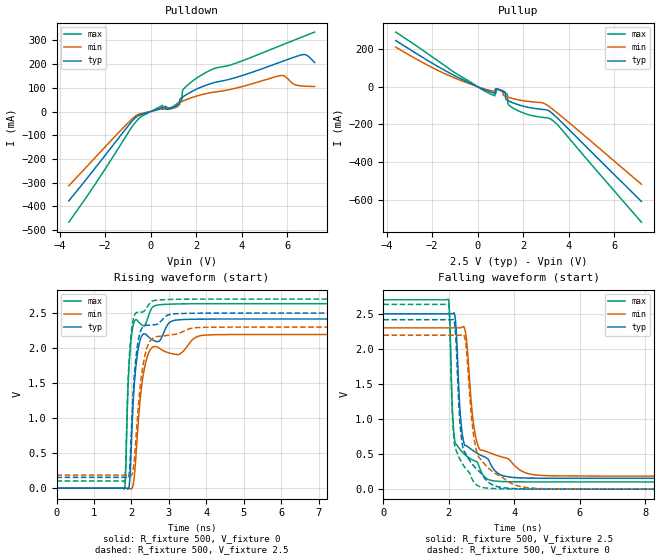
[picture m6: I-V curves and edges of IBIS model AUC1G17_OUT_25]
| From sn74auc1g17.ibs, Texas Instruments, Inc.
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[Model]   AUC1G17_OUT_25
Model_type  Output
Vref =   0
Rref =   500
Cref =   30p
Vmeas =   1.25
| variable   typ   min   max
C_comp   4.92pF   0.40pF   11.11pF
| C_pullup   5.21pF   0.40pF   11.11pF
| C_pulldown   4.64pF   0.49pF   6.59pF
[Temperature Range]   40   100   -40
| Ambient temperature   25   85   -40
[Voltage range]   2.5   2.3   2.7
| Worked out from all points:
|   slope of the pulldown table from 0 to 0.375 V, typ, clamps not added: 30.9 ohm
|   slope of the pullup table from 0 to 0.375 V, typ, clamps not added: 19.1 ohm
|   rising waveform, R_fixture 500, V_fixture 0: 20-80 % time 177ps typ, 248ps min, 128ps max; typ from 0 V to 2.42 V
|   falling waveform, R_fixture 500, V_fixture 2.5: 20-80 % time 235ps typ, 314ps min, 211ps max; typ from 2.5 V to 0.154 V
|   rising waveform, R_fixture 500, V_fixture 2.5: 20-80 % time 175ps typ, 246ps min, 126ps max; typ from 0.154 V to 2.5 V
|   falling waveform, R_fixture 500, V_fixture 0: 20-80 % time 304ps typ, 370ps min, 203ps max; typ from 2.42 V to 0 V
[Pulldown]
| AUC1G17_OUT_25
|   Voltage   I(typ)   I(min)   I(max)
-3.6V     -376.9mA   -313.1mA   -466.8mA
-450mV    -13.55mA   -9.198mA   -23.42mA
515mV     17.02mA    12.57mA    25.99mA
1.025V    18.9mA     15.4mA     23.61mA
1.27V     30.1mA     38.43mA    41.47mA
1.37V     59.42mA    42.49mA    49.07mA
1.395V    60.94mA    43.5mA     85.27mA
1.48V     66.06mA    46.86mA    98.94mA
2.54V     114.8mA    77.9mA     170.7mA
5.695V    208.5mA    151.4mA    277.9mA
6.74V     240.5mA    107.1mA    317.9mA
7.2V      207mA      105.8mA    335.2mA
[Pullup]
| AUC1G17_OUT_25
|   Voltage   I(typ)   I(min)   I(max)
-3.6V     245.6mA    210.5mA    290.4mA
295mV     -15.8mA    -11.56mA   -21.97mA
750mV     -34.5mA    -24.9mA    -48.13mA
770mV     -35.18mA   -25.36mA   -13.07mA
1.115V    -23.95mA   -20.34mA   -27.78mA
1.215V    -28.93mA   -50.57mA   -34.8mA
1.235V    -63.85mA   -51.41mA   -36.2mA
1.295V    -71.17mA   -53.86mA   -40.35mA
1.34V     -74.13mA   -55.63mA   -92.46mA
1.59V     -87.28mA   -64.24mA   -115.7mA
3.275V    -140.8mA   -117.4mA   -177.3mA
7.2V      -609.8mA   -518.6mA   -720mA
[Ramp]
| AUC1G17_OUT_25
| variable   typ   min   max
dV/dt_r   1.46/1.77E-10   1.33/2.49E-10   1.59/1.28E-10
dV/dt_f   1.42/2.34E-10   1.28/3.14E-10   1.56/2.09E-10
R_load = 500
[Rising Waveform]
| AUC1G17_OUT_25
R_fixture =   500
C_fixture =   0
L_fixture =   0
V_fixture =   0
V_fixture_min = 0
V_fixture_max = 0
|   Time   V(typ)   V(min)   V(max)
0s        8.521nV    24.59nV    1.794nV
1.81ns    228.4uV    -51.97uV   -8.382mV
1.84ns    2.634uV    -263.2uV   145.3mV
1.945ns   54.68mV    -3.046mV   1.809V
2.035ns   1.091V     18.31mV    2.292V
2.16ns    1.915V     768.5mV    2.395V
2.335ns   2.204V     1.675V     2.316V
2.71ns    2.093V     2.012V     2.616V
3.67ns    2.412V     2.138V     2.633V
34.99ns   2.416V     2.195V     2.634V
[Falling Waveform]
| AUC1G17_OUT_25
R_fixture =   500
C_fixture =   0
L_fixture =   0
V_fixture =   2.5
V_fixture_min = 2.3
V_fixture_max = 2.7
|   Time   V(typ)   V(min)   V(max)
0s        2.5V       2.3V       2.7V
1.99ns    2.5V       2.3V       2.705V
2.11ns    2.502V     2.3V       1.117V
2.19ns    2.454V     2.3V       662.6mV
2.345ns   1.098V     2.3V       564.7mV
2.465ns   648.7mV    2.31V      502mV
2.835ns   520.7mV    713.4mV    394mV
3.355ns   294.4mV    499.6mV    119.3mV
5.105ns   154.9mV    190.6mV    102.7mV
34.99ns   154.5mV    186.3mV    102.6mV
[Rising Waveform]
| AUC1G17_OUT_25
R_fixture =   500
C_fixture =   0
L_fixture =   0
V_fixture =   2.5
V_fixture_min = 2.3
V_fixture_max = 2.7
|   Time   V(typ)   V(min)   V(max)
0s        154.5mV    186.3mV    102.6mV
1.815ns   154.7mV    186.2mV    94.86mV
1.845ns   154.4mV    186.1mV    291.3mV
1.9ns     141.9mV    185.8mV    1.371V
1.94ns    196.8mV    184.9mV    1.837V
2.03ns    1.196V     215.2mV    2.359V
2.155ns   2.017V     958.3mV    2.51V
2.315ns   2.309V     1.767V     2.52V
2.65ns    2.335V     2.161V     2.682V
34.99ns   2.5V       2.3V       2.7V
[Falling Waveform]
| AUC1G17_OUT_25
R_fixture =   500
C_fixture =   0
L_fixture =   0
V_fixture =   0
V_fixture_min = 0
V_fixture_max = 0
|   Time   V(typ)   V(min)   V(max)
0s        2.416V     2.195V     2.634V
1.99ns    2.416V     2.195V     2.636V
2.105ns   2.417V     2.195V     1.087V
2.185ns   2.326V     2.195V     599.9mV
2.325ns   1.039V     2.195V     439.3mV
2.43ns    588.7mV    2.204V     350.4mV
2.79ns    315.8mV    671mV      85.72mV
3.095ns   152.9mV    355.5mV    19.4mV
5.05ns    284.1uV    4.26mV     -89.41uV
34.99ns   11.81uV    34.1nV     5.711uV
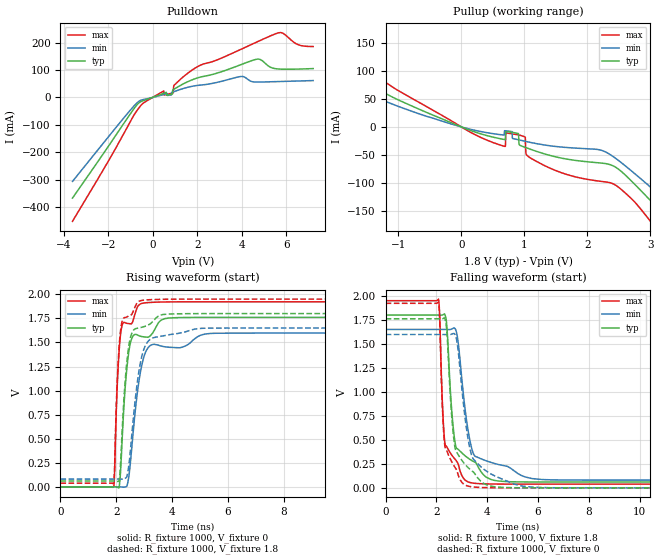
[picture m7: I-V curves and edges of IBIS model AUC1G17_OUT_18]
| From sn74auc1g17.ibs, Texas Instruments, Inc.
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[Model]   AUC1G17_OUT_18
Model_type  Output
Vref =   0
Rref =   1000
Cref =   30p
Vmeas =   0.9
| variable   typ   min   max
C_comp   5.30pF   0.54pF   7.90pF
| C_pullup   4.83pF   0.54pF   7.90pF
| C_pulldown   5.77pF   2.99pF   7.75pF
[Temperature Range]   40   100   -40
| Ambient temperature   25   85   -40
[Voltage range]   1.8   1.65   1.95
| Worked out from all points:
|   slope of the pulldown table from 0 to 0.27 V, typ, clamps not added: 34.4 ohm
|   slope of the pullup table from 0 to 0.27 V, typ, clamps not added: 24.6 ohm
|   rising waveform, R_fixture 1000, V_fixture 0: 20-80 % time 264ps typ, 398ps min, 176ps max; typ from 0 V to 1.76 V
|   falling waveform, R_fixture 1000, V_fixture 1.8: 20-80 % time 341ps typ, 479ps min, 266ps max; typ from 1.8 V to 0.061 V
|   rising waveform, R_fixture 1000, V_fixture 1.8: 20-80 % time 260ps typ, 387ps min, 172ps max; typ from 0.061 V to 1.8 V
|   falling waveform, R_fixture 1000, V_fixture 0: 20-80 % time 383ps typ, 501ps min, 259ps max; typ from 1.76 V to 0 V
[Pulldown]
| AUC1G17_OUT_18
|   Voltage   I(typ)   I(min)   I(max)
-3.6V     -366.8mA   -306mA     -451.3mA
-840mV    -41.02mA   -31.27mA   -64.29mA
-415mV    -11.62mA   -7.635mA   -20.14mA
495mV     14.95mA    10.62mA    23.51mA
885mV     12.29mA    19.09mA    15.87mA
925mV     28.57mA    20.19mA    16.9mA
960mV     30.15mA    21.18mA    44.34mA
2.04V     71.84mA    43.97mA    113.3mA
3.92V     118.2mA    75.81mA    173.7mA
4.62V     138.3mA    55.96mA    199.9mA
5.58V     103.9mA    57.6mA     233.8mA
7.2V      105mA      61.31mA    185.3mA
[Pullup]
| AUC1G17_OUT_18
|   Voltage   I(typ)   I(min)   I(max)
-3.6V     219.7mA    181.5mA    263.9mA
-2.435V   137.9mA    110.1mA    175mA
185mV     -7.816mA   -5.25mA    -11.89mA
695mV     -22.64mA   -6.828mA   -34.84mA
705mV     -8.169mA   -6.943mA   -10.57mA
905mV     -11.83mA   -22.82mA   -14.13mA
970mV     -34.54mA   -24.44mA   -16.12mA
1.11V     -40.27mA   -27.85mA   -56.21mA
2.24V     -64.51mA   -42.18mA   -97.18mA
3.14V     -147.4mA   -120.7mA   -187.8mA
3.745V    -219.6mA   -181.2mA   -274mA
7.2V      -629.9mA   -534.2mA   -754.2mA
[Ramp]
| AUC1G17_OUT_18
| variable   typ   min   max
dV/dt_r   1.06/2.66E-10   0.96/3.99E-10   1.16/1.76E-10
dV/dt_f   1.05/3.38E-10   0.95/4.82E-10   1.16/2.60E-10
R_load = 1000
[Rising Waveform]
| AUC1G17_OUT_18
R_fixture =   1000
C_fixture =   0
L_fixture =   0
V_fixture =   0
V_fixture_min = 0
V_fixture_max = 0
|   Time   V(typ)   V(min)   V(max)
0s        6.666nV    22.4nV     1.077nV
1.91ns    204.4uV    -5.316uV   2.748mV
2.045ns   -5.381mV   303.5uV    1.123V
2.175ns   283.2mV    -271.2uV   1.631V
2.315ns   1.019V     -757.5uV   1.705V
2.47ns    1.444V     156.6mV    1.696V
2.74ns    1.58V      947.8mV    1.858V
2.97ns    1.559V     1.332V     1.909V
5.56ns    1.761V     1.596V     1.922V
34.99ns   1.761V     1.597V     1.922V
[Falling Waveform]
| AUC1G17_OUT_18
R_fixture =   1000
C_fixture =   0
L_fixture =   0
V_fixture =   1.8
V_fixture_min = 1.65
V_fixture_max = 1.95
|   Time   V(typ)   V(min)   V(max)
0s        1.8V       1.65V      1.95V
2.08ns    1.8V       1.65V      1.966V
2.125ns   1.8V       1.65V      1.807V
2.245ns   1.801V     1.65V      820.5mV
2.34ns    1.8V       1.65V      454mV
2.74ns    463.2mV    1.657V     296.1mV
3.345ns   292.1mV    460.2mV    54.05mV
4.145ns   87.29mV    265.3mV    40.19mV
6.15ns    61mV       86.77mV    38.59mV
34.99ns   61.06mV    81.2mV     38.69mV
[Rising Waveform]
| AUC1G17_OUT_18
R_fixture =   1000
C_fixture =   0
L_fixture =   0
V_fixture =   1.8
V_fixture_min = 1.65
V_fixture_max = 1.95
|   Time   V(typ)   V(min)   V(max)
0s        61.05mV    81.2mV     38.68mV
1.91ns    61.22mV    81.2mV     44.64mV
2.04ns    56.69mV    81.44mV    1.138V
2.17ns    344mV      81.15mV    1.664V
2.305ns   1.051V     85.56mV    1.759V
2.455ns   1.479V     240.3mV    1.777V
2.9ns     1.657V     1.341V     1.936V
3.285ns   1.712V     1.544V     1.945V
5.18ns    1.8V       1.648V     1.95V
34.99ns   1.8V       1.65V      1.95V
[Falling Waveform]
| AUC1G17_OUT_18
R_fixture =   1000
C_fixture =   0
L_fixture =   0
V_fixture =   0
V_fixture_min = 0
V_fixture_max = 0
|   Time   V(typ)   V(min)   V(max)
0s        1.761V     1.597V     1.922V
2.08ns    1.761V     1.597V     1.936V
2.125ns   1.761V     1.597V     1.77V
2.245ns   1.762V     1.597V     780.1mV
2.335ns   1.76V      1.597V     430.1mV
2.725ns   430.3mV    1.601V     216.3mV
3.285ns   201.3mV    452.4mV    15.43mV
3.995ns   28.75mV    169.5mV    2.059mV
5.825ns   71.74uV    6.139mV    -90.54uV
34.99ns   14.24uV    146.2nV    6.581uV
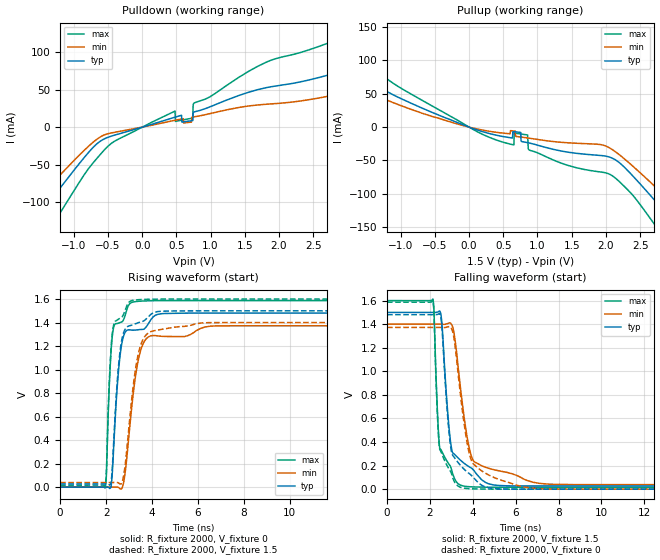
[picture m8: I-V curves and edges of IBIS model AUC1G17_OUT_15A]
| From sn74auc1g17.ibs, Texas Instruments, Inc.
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[Model]   AUC1G17_OUT_15A
Model_type  Output
Vref =   0
Rref =   2000
Cref =   15p
Vmeas =   0.75
| variable   typ   min   max
C_comp   6.54pF   0.01pF   14.87pF
| C_pullup   4.73pF   0.01pF   9.04pF
| C_pulldown   8.34pF   2.16pF   14.87pF
[Temperature Range]   40   100   -40
| Ambient temperature   25   85   -40
[Voltage range]   1.5   1.4   1.6
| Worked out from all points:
|   slope of the pulldown table from 0 to 0.225 V, typ, clamps not added: 36.6 ohm
|   slope of the pullup table from 0 to 0.225 V, typ, clamps not added: 29.5 ohm
|   rising waveform, R_fixture 2000, V_fixture 0: 20-80 % time 333ps typ, 507ps min, 216ps max; typ from 0 V to 1.48 V
|   falling waveform, R_fixture 2000, V_fixture 1.5: 20-80 % time 404ps typ, 621ps min, 291ps max; typ from 1.5 V to 0.027 V
|   rising waveform, R_fixture 2000, V_fixture 1.5: 20-80 % time 328ps typ, 499ps min, 212ps max; typ from 0.027 V to 1.5 V
|   falling waveform, R_fixture 2000, V_fixture 0: 20-80 % time 411ps typ, 629ps min, 289ps max; typ from 1.48 V to 0 V
[Pulldown]
| AUC1G17_OUT_15A
|   Voltage   I(typ)   I(min)   I(max)
-3.6V     -362.2mA   -303.1mA   -443.9mA
-2.135V   -191.7mA   -156.1mA   -245.5mA
-1.82V    -154.7mA   -124.7mA   -202.3mA
-1.36V    -100.1mA   -79.29mA   -137.6mA
-405mV    -10.71mA   -6.927mA   -18.81mA
480mV     13.33mA    9.224mA    21.44mA
485mV     13.46mA    9.315mA    7.619mA
735mV     8.725mA    13.4mA     12.06mA
755mV     20.22mA    13.7mA     32.02mA
1.69V     50.1mA     29.63mA    81.31mA
3.34V     86.08mA    49.9mA     134.3mA
7.2V      80.61mA    45.5mA     141.2mA
[Pullup]
| AUC1G17_OUT_15A
|   Voltage   I(typ)   I(min)   I(max)
-3.6V     206.3mA    154.7mA    250mA
-2.74V    148.1mA    117.2mA    186.2mA
-2.285V   118.2mA    92.64mA    152.4mA
115mV     -4.163mA   -2.727mA   -6.621mA
650mV     -6.722mA   -5.655mA   -26.6mA
660mV     -6.84mA    -5.748mA   -8.817mA
855mV     -23.23mA   -16.19mA   -11.7mA
885mV     -23.9mA    -16.64mA   -34.51mA
2.09V     -46.33mA   -33.39mA   -72.65mA
2.73V     -111.6mA   -90.11mA   -148.4mA
3.345V    -184.2mA   -150.7mA   -235.6mA
7.2V      -639.9mA   -542.7mA   -769.8mA
[Ramp]
| AUC1G17_OUT_15A
| variable   typ   min   max
dV/dt_r   0.90/3.34E-10   0.83/5.11E-10   0.96/2.18E-10
dV/dt_f   0.89/4.07E-10   0.82/6.36E-10   0.96/2.83E-10
R_load = 2000
[Rising Waveform]
| AUC1G17_OUT_15A
R_fixture =   2000
C_fixture =   0
L_fixture =   0
V_fixture =   0
V_fixture_min = 0
V_fixture_max = 0
|   Time   V(typ)   V(min)   V(max)
0s        6.115nV    22.54nV    845pV
1.955ns   42.64uV    -2uV       -7.903mV
2.01ns    39.38uV    -4.443uV   95.5mV
2.17ns    -10.84mV   -14.81uV   994.8mV
2.295ns   204.7mV    370.5uV    1.323V
2.655ns   1.189V     -17.51mV   1.404V
3.175ns   1.335V     784.7mV    1.575V
3.78ns    1.373V     1.268V     1.585V
6.53ns    1.481V     1.369V     1.587V
34.99ns   1.481V     1.373V     1.587V
[Falling Waveform]
| AUC1G17_OUT_15A
R_fixture =   2000
C_fixture =   0
L_fixture =   0
V_fixture =   1.5
V_fixture_min = 1.4
V_fixture_max = 1.6
|   Time   V(typ)   V(min)   V(max)
0s        1.5V       1.4V       1.6V
2.14ns    1.5V       1.4V       1.613V
2.195ns   1.5V       1.4V       1.483V
2.36ns    1.503V     1.4V       620.1mV
2.46ns    1.51V      1.4V       348.9mV
2.985ns   371.8mV    1.404V     179.9mV
3.525ns   229.9mV    709.5mV    28.29mV
4.055ns   157.4mV    234.2mV    18.95mV
7.105ns   27.11mV    49.11mV    16.41mV
34.99ns   27.19mV    38.78mV    16.41mV
[Rising Waveform]
| AUC1G17_OUT_15A
R_fixture =   2000
C_fixture =   0
L_fixture =   0
V_fixture =   1.5
V_fixture_min = 1.4
V_fixture_max = 1.6
|   Time   V(typ)   V(min)   V(max)
0s        27.17mV    38.78mV    16.4mV
1.955ns   27.21mV    38.78mV    8.776mV
2.01ns    27.21mV    38.77mV    117.8mV
2.165ns   17.43mV    38.77mV    1.003V
2.29ns    230.4mV    39.09mV    1.339V
2.635ns   1.196V     26.31mV    1.443V
3.155ns   1.381V     817.1mV    1.589V
3.745ns   1.431V     1.296V     1.598V
6.155ns   1.5V       1.397V     1.6V
34.99ns   1.5V       1.4V       1.6V
[Falling Waveform]
| AUC1G17_OUT_15A
R_fixture =   2000
C_fixture =   0
L_fixture =   0
V_fixture =   0
V_fixture_min = 0
V_fixture_max = 0
|   Time   V(typ)   V(min)   V(max)
0s        1.481V     1.373V     1.587V
2.14ns    1.481V     1.373V     1.599V
2.355ns   1.483V     1.373V     613.6mV
2.45ns    1.49V      1.373V     345mV
2.555ns   1.385V     1.372V     300.5mV
2.97ns    357.1mV    1.374V     149.4mV
3.475ns   191.8mV    725mV      12.64mV
4.005ns   103.3mV    218mV      2.656mV
6.63ns    -42.84uV   10.74mV    -29.27uV
34.99ns   16.27uV    97.67nV    7.159uV
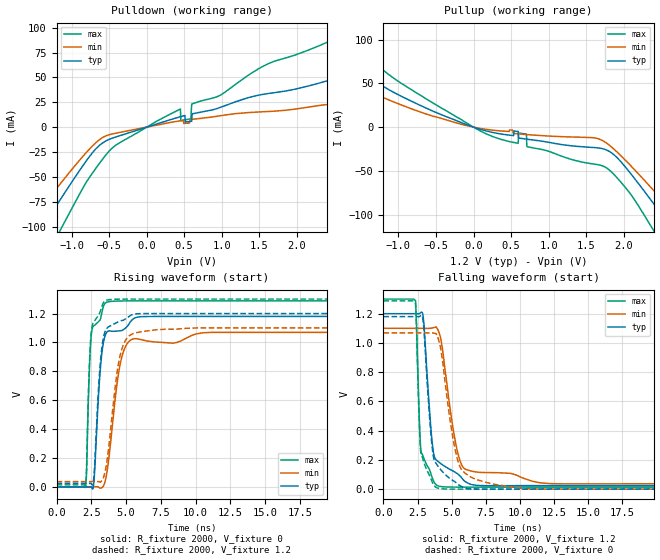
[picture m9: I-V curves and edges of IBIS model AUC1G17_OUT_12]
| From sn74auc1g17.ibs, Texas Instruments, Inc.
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[Model]   AUC1G17_OUT_12
Model_type  Output
Vref =   0
Rref =   2000
Cref =   15p
Vmeas =   0.6
| variable   typ   min   max
C_comp   8.54pF   0.76pF   20.63pF
| C_pullup   6.16pF   0.76pF   15.52pF
| C_pulldown   10.91pF   4.25pF   20.63pF
[Temperature Range]   40   100   -40
| Ambient temperature   25   85   -40
[Voltage range]   1.2   1.1   1.3
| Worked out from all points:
|   slope of the pulldown table from 0 to 0.18 V, typ, clamps not added: 41.7 ohm
|   slope of the pullup table from 0 to 0.18 V, typ, clamps not added: 38.9 ohm
|   rising waveform, R_fixture 2000, V_fixture 0: 20-80 % time 476ps typ, 809ps min, 280ps max; typ from 0 V to 1.18 V
|   falling waveform, R_fixture 2000, V_fixture 1.2: 20-80 % time 571ps typ, 1.02ns min, 286ps max; typ from 1.2 V to 0.024 V
|   rising waveform, R_fixture 2000, V_fixture 1.2: 20-80 % time 466ps typ, 804ps min, 275ps max; typ from 0.024 V to 1.2 V
|   falling waveform, R_fixture 2000, V_fixture 0: 20-80 % time 573ps typ, 1.04ns min, 284ps max; typ from 1.18 V to 0 V
[Pulldown]
| AUC1G17_OUT_12
|   Voltage   I(typ)   I(min)   I(max)
-3.6V     -357.6mA   -299.6mA   -437.6mA
-1.74V    -141.5mA   -113.9mA   -185.5mA
-1.425V   -104.7mA   -83.18mA   -142.1mA
-1.205V   -79.17mA   -62.08mA   -111.4mA
-680mV    -22.07mA   -15.93mA   -41.78mA
-400mV    -9.617mA   -5.913mA   -17.55mA
450mV     10.5mA     6.398mA    18.24mA
590mV     5.848mA    7.731mA    8.546mA
605mV     12.96mA    7.861mA    23.36mA
2.86V     55.95mA    19.1mA     100.7mA
3.425V    44.58mA    20.08mA    119.3mA
7.2V      57.06mA    26.83mA    108mA
[Pullup]
| AUC1G17_OUT_12
|   Voltage   I(typ)   I(min)   I(max)
-3.6V     176.4mA    42.49mA    236.9mA
-2.43V    115.8mA    55.94mA    152.3mA
-1.99V    89.62mA    64.91mA    120.7mA
90mV      -2.485mA   -1.46mA    -4.344mA
595mV     -5.009mA   -7.72mA    -18.47mA
700mV     -13.68mA   -8.451mA   -7.891mA
720mV     -13.91mA   -8.58mA    -22.52mA
1.785V    -26.75mA   -19.12mA   -47.45mA
2.43V     -91.21mA   -75.43mA   -122.7mA
2.725V    -125.6mA   -103.9mA   -164.5mA
3.075V    -166.8mA   -138.4mA   -213.7mA
7.2V      -651.6mA   -555.8mA   -783.1mA
[Ramp]
| AUC1G17_OUT_12
| variable   typ   min   max
dV/dt_r   0.72/4.81E-10   0.65/8.33E-10   0.78/2.81E-10
dV/dt_f   0.71/5.75E-10   0.64/1.05E-09   0.77/2.89E-10
R_load = 2000
[Rising Waveform]
| AUC1G17_OUT_12
R_fixture =   2000
C_fixture =   0
L_fixture =   0
V_fixture =   0
V_fixture_min = 0
V_fixture_max = 0
|   Time   V(typ)   V(min)   V(max)
0s        5.712nV    23.9nV     679pV
2.075ns   -4.203uV   -1.056uV   -4.337mV
2.15ns    -7.119uV   -1.391uV   75.72mV
2.415ns   -121.3uV   -42.71uV   928.1mV
2.63ns    -9.651mV   286.8uV    1.11V
3.17ns    836.3mV    -8.525mV   1.165V
3.605ns   1.069V     88.42mV    1.278V
4.56ns    1.08V      839.8mV    1.287V
5.495ns   1.161V     1.023V     1.288V
34.99ns   1.18V      1.069V     1.287V
[Falling Waveform]
| AUC1G17_OUT_12
R_fixture =   2000
C_fixture =   0
L_fixture =   0
V_fixture =   1.2
V_fixture_min = 1.1
V_fixture_max = 1.3
|   Time   V(typ)   V(min)   V(max)
0s        1.2V       1.1V       1.3V
2.35ns    1.2V       1.1V       1.289V
2.64ns    1.2V       1.1V       458.2mV
2.75ns    1.209V     1.1V       260.3mV
2.96ns    1.138V     1.1V       212.1mV
3.605ns   295.8mV    1.103V     72.12mV
4.03ns    187.5mV    1.083V     21.57mV
5.31ns    112.8mV    308.2mV    14.09mV
6.04ns    49.2mV     134.6mV    13.86mV
34.99ns   24mV       36.65mV    13.87mV
[Rising Waveform]
| AUC1G17_OUT_12
R_fixture =   2000
C_fixture =   0
L_fixture =   0
V_fixture =   1.2
V_fixture_min = 1.1
V_fixture_max = 1.3
|   Time   V(typ)   V(min)   V(max)
0s        23.98mV    36.64mV    13.86mV
2.075ns   23.97mV    36.64mV    9.876mV
2.15ns    23.97mV    36.64mV    97.7mV
2.4ns     24.12mV    36.62mV    923.6mV
2.615ns   17.32mV    36.88mV    1.131V
3.15ns    857.3mV    32.64mV    1.215V
3.555ns   1.088V     135.1mV    1.291V
4.535ns   1.146V     891.4mV    1.299V
5.6ns     1.196V     1.064V     1.3V
34.99ns   1.2V       1.1V       1.3V
[Falling Waveform]
| AUC1G17_OUT_12
R_fixture =   2000
C_fixture =   0
L_fixture =   0
V_fixture =   0
V_fixture_min = 0
V_fixture_max = 0
|   Time   V(typ)   V(min)   V(max)
0s        1.18V      1.069V     1.287V
2.35ns    1.18V      1.069V     1.272V
2.625ns   1.179V     1.069V     469mV
2.74ns    1.186V     1.069V     250.9mV
2.955ns   1.108V     1.069V     187.2mV
3.565ns   292.9mV    1.069V     50.74mV
3.95ns    163.9mV    1.047V     8.2mV
5.43ns    36.39mV    203.6mV    139.7uV
6.86ns    468.6uV    64.38mV    -7.816uV
34.99ns   19.54uV    917.8nV    7.827uV
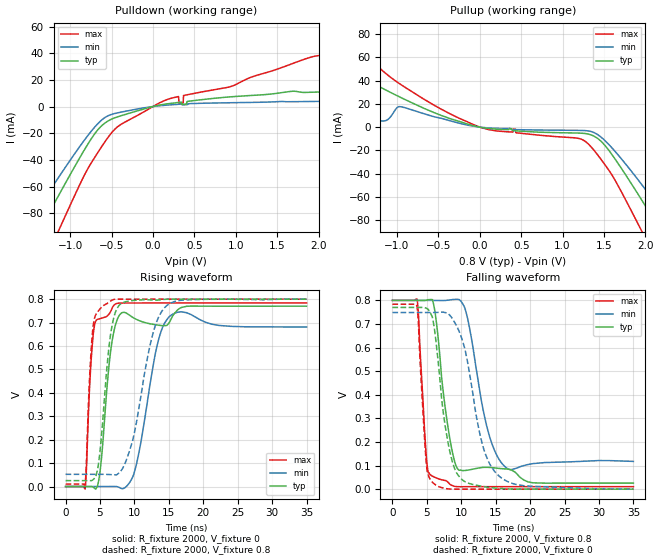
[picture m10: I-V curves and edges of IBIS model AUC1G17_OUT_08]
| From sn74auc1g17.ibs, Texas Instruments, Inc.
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[Model]   AUC1G17_OUT_08
Model_type  Output
Vref =   0
Rref =   2000
Cref =   15p
Vmeas =   0.4
| variable   typ   min   max
C_comp   11.50pF   4.31pF   28.06pF
| C_pullup   9.94pF   4.31pF   19.88pF
| C_pulldown   13.05pF   5.59pF   28.06pF
[Temperature Range]   40   100   -40
| Ambient temperature   25   85   -40
[Voltage range]   0.8   0.8   0.8
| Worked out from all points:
|   slope of the pulldown table from 0 to 0.12 V, typ, clamps not added: 77.1 ohm
|   slope of the pullup table from 0 to 0.12 V, typ, clamps not added: 92.3 ohm
|   rising waveform, R_fixture 2000, V_fixture 0: 20-80 % time 1.41ns typ, 2.3ns min, 812ps max; typ from 0 V to 0.77 V
|   falling waveform, R_fixture 2000, V_fixture 0.8: 20-80 % time 1.92ns typ, 2.49ns min, 918ps max; typ from 0.8 V to 0.026 V
|   rising waveform, R_fixture 2000, V_fixture 0.8: 20-80 % time 1.42ns typ, 2.89ns min, 760ps max; typ from 0.025 V to 0.8 V
|   falling waveform, R_fixture 2000, V_fixture 0: 20-80 % time 2.02ns typ, 3.02ns min, 907ps max; typ from 0.77 V to 0 V
[Pulldown]
| AUC1G17_OUT_08
|   Voltage   I(typ)   I(min)   I(max)
-3.6V     -351.4mA   -296mA     -426.9mA
-1.64V    -124.2mA   -100.9mA   -161.6mA
-1.505V   -108.6mA   -87.85mA   -143.2mA
-1.38V    -94.21mA   -75.85mA   -126.1mA
-1.16V    -69.1mA    -55.05mA   -95.95mA
-645mV    -16.01mA   -11.59mA   -32.55mA
-435mV    -7.893mA   -4.858mA   -15.6mA
-95mV     -1.581mA   -843.7uA   -3.47mA
210mV     2.329mA    1.254mA    6.027mA
1.98V     10.84mA    3.867mA    38.03mA
2.365V    11.74mA    4.199mA    33.49mA
7.2V      23.85mA    8.894mA    59.34mA
[Pullup]
| AUC1G17_OUT_08
|   Voltage   I(typ)   I(min)   I(max)
-3.6V     28.84mA    5.54mA     124.5mA
-1.765V   21.99mA    5.716mA    86.03mA
-1.295V   37.02mA    6.071mA    56.08mA
-1.125V   31.49mA    5.853mA    45.48mA
-970mV    25.97mA    17.63mA    37.33mA
-245mV    4.854mA    3.296mA    7.479mA
1.31V     -5.923mA   -3.24mA    -14.41mA
1.515V    -16.03mA   -11.81mA   -32.61mA
1.89V     -55.16mA   -43.2mA    -80.11mA
2.125V    -81.81mA   -65.03mA   -112.8mA
2.4V      -113.5mA   -91.33mA   -150.9mA
7.2V      -672.5mA   -573.3mA   -806.8mA
[Ramp]
| AUC1G17_OUT_08
| variable   typ   min   max
dV/dt_r   0.47/1.47E-09   0.45/2.65E-09   0.48/8.23E-10
dV/dt_f   0.47/1.97E-09   0.43/2.76E-09   0.48/9.31E-10
R_load = 2000
[Rising Waveform]
| AUC1G17_OUT_08
R_fixture =   2000
C_fixture =   0
L_fixture =   0
V_fixture =   0
V_fixture_min = 0
V_fixture_max = 0
|   Time   V(typ)   V(min)   V(max)
0s        6.987nV    39nV       506.4pV
2.835ns   -33.44uV   -2.943uV   -10.55mV
3.795ns   86.36uV    -8.589uV   572.9mV
4.67ns    6.45mV     -11.9uV    714.4mV
6.365ns   532.8mV    314.3uV    738.6mV
7.145ns   679mV      295.3uV    777.2mV
9.895ns   719.8mV    52.25mV    783.6mV
13.25ns   690.2mV    596.4mV    783.7mV
15.17ns   705.7mV    728.2mV    783.7mV
34.99ns   770mV      680.9mV    783.8mV
[Falling Waveform]
| AUC1G17_OUT_08
R_fixture =   2000
C_fixture =   0
L_fixture =   0
V_fixture =   0.8
V_fixture_min = 0.8
V_fixture_max = 0.8
|   Time   V(typ)   V(min)   V(max)
0s        800mV      800mV      800mV
3.575ns   800mV      800mV      805.6mV
4.92ns    801mV      800mV      137.6mV
5.59ns    803.4mV    800mV      58.95mV
8.2ns     237.8mV    801.5mV    25.39mV
9.58ns    82.33mV    804.3mV    10.62mV
10.92ns   80.5mV     723.8mV    10.49mV
13.95ns   92.36mV    238.8mV    10.64mV
16.33ns   85.85mV    95.65mV    10.63mV
34.99ns   25.53mV    117.6mV    10.61mV
[Rising Waveform]
| AUC1G17_OUT_08
R_fixture =   2000
C_fixture =   0
L_fixture =   0
V_fixture =   0.8
V_fixture_min = 0.8
V_fixture_max = 0.8
|   Time   V(typ)   V(min)   V(max)
0s        25.46mV    52.25mV    10.6mV
2.835ns   25.46mV    52.25mV    9.132mV
3.945ns   28.38mV    52.28mV    668.4mV
4.72ns    85.31mV    52.32mV    748.1mV
5.485ns   315mV      52.26mV    772.2mV
6.44ns    628.5mV    51.26mV    790.4mV
7.485ns   761.2mV    51.52mV    800mV
12.86ns   796.1mV    671.3mV    799.9mV
14.75ns   799.8mV    773.6mV    799.9mV
34.99ns   800mV      800.3mV    800mV
[Falling Waveform]
| AUC1G17_OUT_08
R_fixture =   2000
C_fixture =   0
L_fixture =   0
V_fixture =   0
V_fixture_min = 0
V_fixture_max = 0
|   Time   V(typ)   V(min)   V(max)
0s        770mV      748.6mV    783.8mV
3.575ns   770mV      748.6mV    773.5mV
4.925ns   766.5mV    748.6mV    108.4mV
6.05ns    687.7mV    748.7mV    22.71mV
7.24ns    359mV      750.4mV    5.928mV
8.065ns   198.5mV    744.2mV    1.282mV
10.18ns   38.77mV    628.7mV    10.85uV
13.06ns   11.6mV     189.8mV    48.52uV
15.53ns   3.505mV    54.13mV    36.52uV
34.99ns   43.5uV     94.84uV    11.7uV
